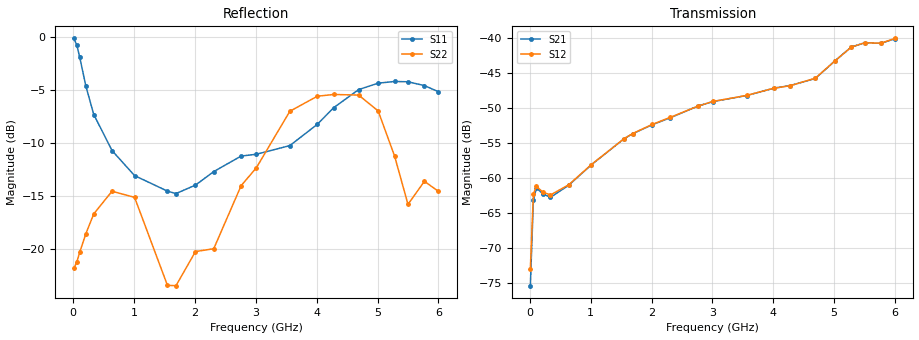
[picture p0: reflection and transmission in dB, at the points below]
!Agilent Technologies,N5230A,MY45001650,A.07.50.48
!Agilent N5230A: A.07.50.48
!Date: Saturday, July 08, 2017 15:47:44
!Correction: S11(Full 2 Port(1,2))
!S21(Full 2 Port(1,2))
!S12(Full 2 Port(1,2))
!S22(Full 2 Port(1,2))
!S2P File: Measurements: S11, S21, S12, S22:
# Hz S  dB  R 50
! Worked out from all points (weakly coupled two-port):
!   600 points, 10 MHz to 6 GHz, reference 50 ohm
!   highest |S21| = -40.07 dB at 6 GHz (marker M1); lowest = -75.4 dB at 10 MHz (marker M2)
!   lowest |S11| = -14.8 dB at 1.69 GHz (marker M3), VSWR 1.45, Z = 34.6 + j1.2 ohm
!   |S11| at or under -10 dB: 553.2 MHz to 3.665 GHz (3.112 GHz wide, 148 % of centre)
!   |S22| runs from -24.0 to -5.3 dB; largest |S21 - S12| = 0.00039
!   S11 on the Smith chart (normalised r, x): 10 MHz: 3, -20; 110 MHz: 0.52, -1.89; 340 MHz: 0.55, -0.54; 2.76 GHz: 0.58, +0.10; 4.28 GHz: 1.40, +1.17; 6 GHz: 2.56, -1.43
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1e7  -0.11 -5.7  -75.37 -137.7  -72.93 -19.7  -21.89 -8.1
6e7  -0.71 -31.6  -63.17 26.8  -62.26 19.3  -21.31 -22.0
1.1e8  -1.91 -53.1  -61.40 -13.6  -61.16 -13.6  -20.34 -37.6
2.1e8  -4.63 -83.7  -62.22 -50.9  -61.98 -50.4  -18.60 -64.0
3.4e8  -7.32 -110.6  -62.75 -80.4  -62.41 -80.1  -16.72 -89.5
6.4e8  -10.73 -148.5  -61.02 -126.2  -60.95 -126.8  -14.58 -127.4
1.01e9  -13.10 -172.4  -58.11 -174.1  -58.08 -174.3  -15.16 -164.1
1.55e9  -14.57 174.2  -54.36 119.4  -54.36 119.4  -23.49 167.7
1.69e9  -14.80 174.7  -53.66 102.4  -53.63 102.4  -23.52 -178.0
2.01e9  -14.00 177.0  -52.38 66.0  -52.33 66.1  -20.29 172.4
2.31e9  -12.72 173.9  -51.37 34.7  -51.31 34.6  -20.02 164.0
2.76e9  -11.25 162.3  -49.71 -12.4  -49.72 -12.4  -14.05 165.3
3.01e9  -11.08 149.5  -49.06 -39.2  -49.04 -39.2  -12.36 158.2
3.56e9  -10.26 106.8  -48.20 -93.9  -48.19 -93.8  -7.01 150.4
4.01e9  -8.25 64.1  -47.15 -136.7  -47.15 -136.7  -5.59 126.7
4.28e9  -6.67 45.0  -46.77 -162.1  -46.79 -162.1  -5.42 113.4
4.69e9  -4.96 24.5  -45.76 167.8  -45.72 167.7  -5.48 81.7
5.01e9  -4.35 13.4  -43.26 140.8  -43.27 140.8  -6.98 46.0
5.28e9  -4.19 5.5  -41.28 108.5  -41.28 108.6  -11.25 17.9
5.5e9  -4.22 -1.3  -40.66 79.8  -40.66 79.9  -15.82 29.0
5.77e9  -4.58 -10.6  -40.74 51.4  -40.72 51.5  -13.64 35.0
6e9  -5.16 -20.6  -40.07 32.9  -40.03 32.6  -14.59 14.3
